One B-rep face of a CAD part: STEP entity #1235.
In plain terms, the planar face has unit normal (1, 0, 0).
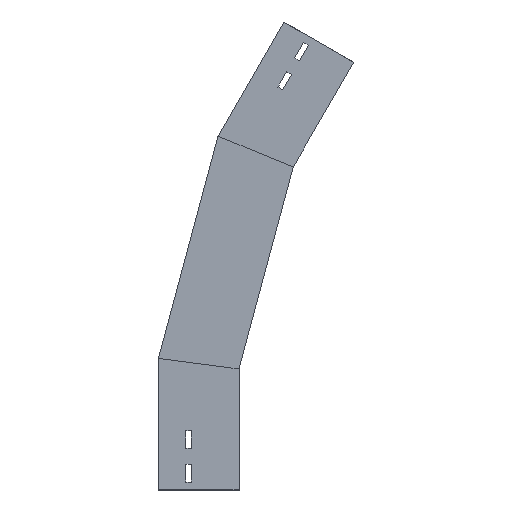
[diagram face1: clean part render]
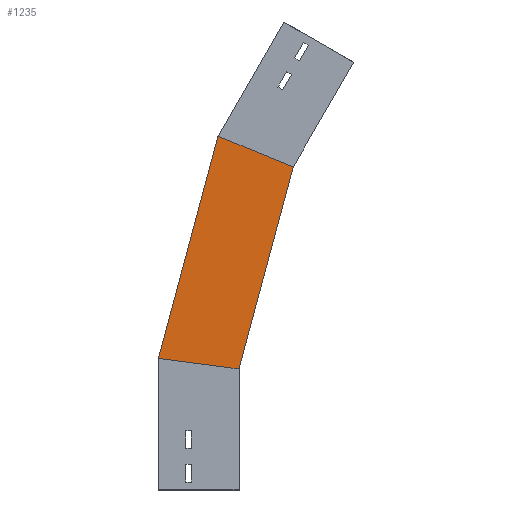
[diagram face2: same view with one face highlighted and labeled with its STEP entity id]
Its self-contained STEP definition (entity closure, numbers rounded to 3 decimals):
#9 = VECTOR ( 'NONE', #652, 1000. ) ;
#26 = CARTESIAN_POINT ( 'NONE',  ( 0., 3.774, 135.915 ) ) ;
#64 = CARTESIAN_POINT ( 'NONE',  ( 0., -67.034, 400.175 ) ) ;
#151 = VECTOR ( 'NONE', #1177, 1000. ) ;
#152 = VECTOR ( 'NONE', #547, 1000. ) ;
#218 = LINE ( 'NONE', #676, #377 ) ;
#236 = EDGE_CURVE ( 'NONE', #1264, #677, #244, .T. ) ;
#244 = LINE ( 'NONE', #933, #151 ) ;
#293 = VERTEX_POINT ( 'NONE', #410 ) ;
#369 = CARTESIAN_POINT ( 'NONE',  ( 0., 0., 150. ) ) ;
#377 = VECTOR ( 'NONE', #1133, 1000. ) ;
#410 = CARTESIAN_POINT ( 'NONE',  ( 0., 100., 163.165 ) ) ;
#495 = DIRECTION ( 'NONE',  ( 1., 0., 0. ) ) ;
#547 = DIRECTION ( 'NONE',  ( 0., -0.924, -0.383 ) ) ;
#652 = DIRECTION ( 'NONE',  ( 0., -0.991, -0.131 ) ) ;
#676 = CARTESIAN_POINT ( 'NONE',  ( 0., 100.367, 161.797 ) ) ;
#677 = VERTEX_POINT ( 'NONE', #64 ) ;
#709 = FACE_OUTER_BOUND ( 'NONE', #1442, .T. ) ;
#779 = ORIENTED_EDGE ( 'NONE', *, *, #1403, .F. ) ;
#786 = ORIENTED_EDGE ( 'NONE', *, *, #236, .F. ) ;
#848 = VERTEX_POINT ( 'NONE', #1408 ) ;
#853 = LINE ( 'NONE', #1478, #9 ) ;
#874 = ORIENTED_EDGE ( 'NONE', *, *, #1477, .T. ) ;
#893 = CARTESIAN_POINT ( 'NONE',  ( 0., -100.025, 386.509 ) ) ;
#919 = EDGE_CURVE ( 'NONE', #848, #677, #1108, .T. ) ;
#933 = CARTESIAN_POINT ( 'NONE',  ( 0., 3.774, 135.915 ) ) ;
#934 = ORIENTED_EDGE ( 'NONE', *, *, #919, .T. ) ;
#941 = DIRECTION ( 'NONE',  ( 0., 0., -1. ) ) ;
#1056 = PLANE ( 'NONE',  #1319 ) ;
#1108 = LINE ( 'NONE', #893, #152 ) ;
#1133 = DIRECTION ( 'NONE',  ( 0., -0.259, 0.966 ) ) ;
#1177 = DIRECTION ( 'NONE',  ( 0., -0.259, 0.966 ) ) ;
#1235 = ADVANCED_FACE ( 'NONE', ( #709 ), #1056, .T. ) ;
#1264 = VERTEX_POINT ( 'NONE', #369 ) ;
#1319 = AXIS2_PLACEMENT_3D ( 'NONE', #26, #495, #941 ) ;
#1403 = EDGE_CURVE ( 'NONE', #293, #1264, #853, .T. ) ;
#1408 = CARTESIAN_POINT ( 'NONE',  ( 0., 26.151, 438.773 ) ) ;
#1442 = EDGE_LOOP ( 'NONE', ( #874, #934, #786, #779 ) ) ;
#1477 = EDGE_CURVE ( 'NONE', #293, #848, #218, .T. ) ;
#1478 = CARTESIAN_POINT ( 'NONE',  ( 0., -19.411, 147.444 ) ) ;
